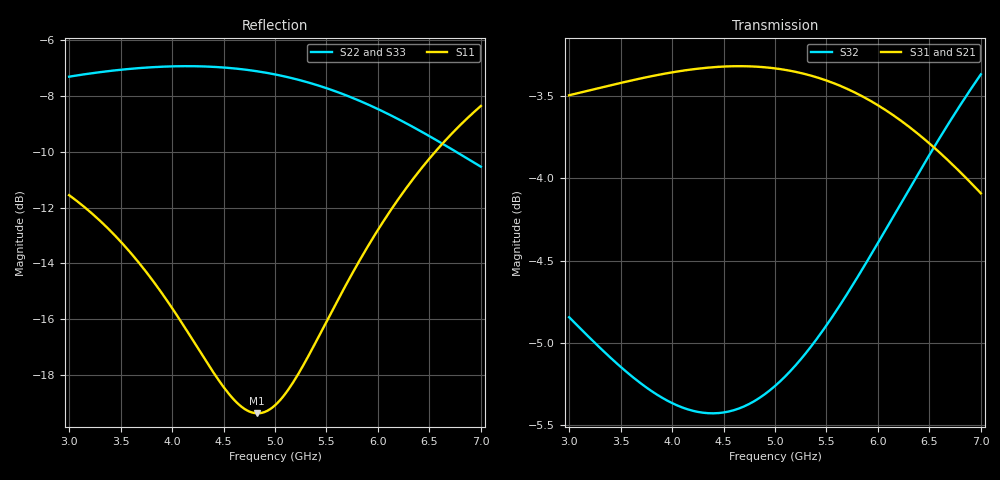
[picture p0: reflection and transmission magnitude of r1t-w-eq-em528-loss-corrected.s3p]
! yapnr Order 0 prediction r1t-w-eq-em528: predictions/references/r1t-w-eq-em528/coarse_dense.s3p, loss-corrected
! substrate W-eq-em528; coupon model OSHPARK-4L-EM528; correction: path [('line', 10.75), ('line', 11.0)] (3.0 mm line's Δα)
! |S21|, |S31| (and S12, S13) scaled, phases kept; 50 ohm, e^(+jwt)
# GHz S RI R 50
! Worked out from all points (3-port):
!   161 points, 3 GHz to 7 GHz, reference 50 ohm
!   strongest paths, dB at 3 GHz, 4 GHz, 5 GHz, 6 GHz, 7 GHz:
!     S31: -3.5, -3.4, -3.3, -3.6, -4.1
!     S21: -3.5, -3.4, -3.3, -3.6, -4.1
!     S32: -4.8, -5.4, -5.3, -4.4, -3.4
!   lowest |S11| = -19.4 dB at 4.825 GHz (marker M1), VSWR 1.24, Z = 61.2 + j4.19 ohm
!   |S11| at or under -10 dB: start of sweep to 6.556 GHz
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3  -0.1538 0.2151  -0.3516 -0.5697  -0.3516 -0.5697
   -0.3511 -0.5691  0.1933 0.3857  -0.4563 -0.3458
   -0.3511 -0.5691  -0.4563 -0.3458  0.1933 0.3857
3.475  -0.0753 0.2076  -0.5329 -0.4148  -0.5329 -0.4148
       -0.5316 -0.4146  0.3438 0.28  -0.5317 -0.155
       -0.5316 -0.4146  -0.5317 -0.155  0.3438 0.28
3.975  0.00547 0.1684  -0.6545 -0.1861  -0.6545 -0.1861
       -0.653 -0.1872  0.4385 0.1012  -0.5377 0.0457
       -0.653 -0.1872  -0.5377 0.0457  0.4385 0.1012
4.4  0.0629 0.1106  -0.6816 0.0386  -0.6816 0.0386
     -0.681 0.0362  0.4432 -0.0737  -0.4955 0.2026
     -0.681 0.0362  -0.4955 0.2026  0.4432 -0.0737
4.825  0.1019 0.0338  -0.6294 0.2626  -0.6294 0.2626
       -0.6308 0.2598  0.3749 -0.2325  -0.4174 0.3433
       -0.6308 0.2598  -0.4174 0.3433  0.3749 -0.2325
5  0.1109 -0.00211  -0.5852 0.3477  -0.5852 0.3477
   -0.5875 0.3452  0.3289 -0.2853  -0.3751 0.3962
   -0.5875 0.3452  -0.3751 0.3962  0.3289 -0.2853
5.525  0.108 -0.118  -0.3849 0.5515  -0.3849 0.5515
       -0.3892 0.5518  0.154 -0.3799  -0.2087 0.5312
       -0.3892 0.5518  -0.2087 0.5312  0.154 -0.3799
6.025  0.0579 -0.2256  -0.1323 0.6456  -0.1323 0.6456
       -0.1354 0.6493  -0.0185 -0.375  0.00758 0.6049
       -0.1354 0.6493  0.00758 0.6049  -0.0185 -0.375
6.525  -0.0383 -0.3091  0.1298 0.6269  0.1298 0.6269
       0.1304 0.6322  -0.1509 -0.2995  0.2638 0.5867
       0.1304 0.6322  0.2638 0.5867  -0.1509 -0.2995
7  -0.1619 -0.3463  0.3428 0.5158  0.3428 0.5158
   0.3467 0.5193  -0.2229 -0.1969  0.5009 0.4577
   0.3467 0.5193  0.5009 0.4577  -0.2229 -0.1969
